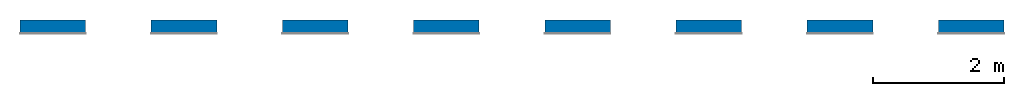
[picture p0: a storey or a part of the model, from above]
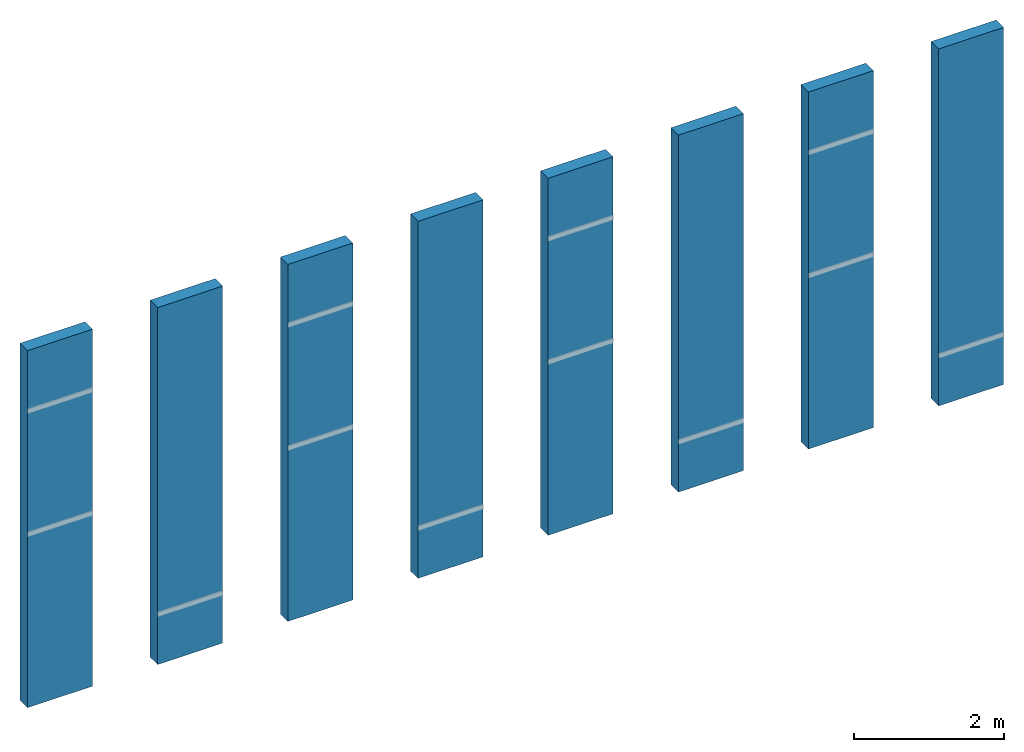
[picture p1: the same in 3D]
Properties of the parts of a building model (IFC4)

# File
Description: ViewDefinition [ReferenceView_V1.2], RevitIdentifiers [VersionGUID: 3b37235f-c921-4a61-a22a-4a3052ba0063, NumberOfSaves: 73], CoordinateReference [CoordinateBase: Shared Coordinates, ProjectSite: Internal]
File name: LOVE TILES-SENSE-SKIRTING.ifc
Time: 2025-04-01T11:52:26
Written by: ODA IFC SDK 22.8
Made in: 22.1.80.32 - IFC 22.7.0.0 - Default UI

# IfcSite, Default
RefLatitude: 42, 24, 53, 508911; RefLongitude: -71, -15, -29, -58837; RefElevation: 0 mm
Text - Library Version: V01
Identity Data - Author: StratBIM; Organization Description: CERAMIC TILES; Organization Name: MARGRES
Other - Category: Project Information; Project Issue Date: 01/2025

# IfcBuilding
Text - Library Version: V01
Identity Data - Author: StratBIM; Organization Description: CERAMIC TILES; Organization Name: MARGRES
Other - Category: Project Information; Project Issue Date: 01/2025

# IfcBuildingStorey: Level:Level 1, Level 1
LongName: Level 1; Elevation: 0 mm
Constraints - Elevation: 0 mm
Dimensions - Computation Height: 0 mm
Identity Data - Structural: no; Building Story: yes; Name: Level 1
Other - Category: Levels; Family: Level; Family and Type: Level: Level 1; Type: Level 1; Type Id: 1604
Constraints(Type) - Elevation Base: Project Base Point
Graphics(Type) - Color: 0; Line Pattern: Solid; Line Weight: 1; Symbol at End 1 Default: no; Symbol at End 2 Default: yes
Identity Data(Type) - Type Name: Level 1
Other(Type) - Category: Levels; Family Name: Level

# IfcBuildingElementProxy: Wall Sweep:LOVE TILES-SENSE-SKIRTING-8X100-IN&OUT RECTIFIED-BEIGE, Wall Sweep:LOVE TILES-SENSE-SKIRTING-8X100-IN&OUT RECTIFIED-BEIGE:47854
In: Level 1
Type - General - BIM Modeler: StratBIM; BIM Modeler URL: www.stratbim.com
Type - Analysis Results - Length per Piece: 1001 mm
Type - Constraints - Cut by Inserts: yes; Cuts Wall: yes; Default Setback: 0 mm
Type - Materials and Finishes - Material: LOVE TILES-SENSE-SKIRTING-8X100-IN&OUT RECTIFIED-BEIGE
Type - Construction - Profile: LOVE TILES-SENSE-SKIRTING-PROFILES : 8x100
Type - Identity Data - Manufacturer: LOVE TILES; Manufacturer URL: https://lovetiles.com/pt; Model: LOVE TILES-SENSE-SKIRTING-8X100-IN&OUT RECTIFIED-BEIGE; Publication date: 01/20025; Type Name: LOVE TILES-SENSE-SKIRTING-8X100-IN&OUT RECTIFIED-BEIGE; URL: https://lovetiles.com/en/products/sense; Version: V01
Type - Other - Category: Walls: Wall Sweeps; Family Name: Wall Sweep
Material: LOVE TILES-SENSE-SKIRTING-8X100-IN&OUT RECTIFIED-BEIGE
Constraints - Level: Level 1; Offset From Wall: 0 mm; Offset From Level: 780 mm
Phasing - Phase Created: New Construction
Dimensions - Length: 1000 mm
Other - Family: Wall Sweep; Family and Type: Wall Sweep: LOVE TILES-SENSE-SKIRTING-8X100-IN&OUT RECTIFIED-BEIGE; Type: LOVE TILES-SENSE-SKIRTING-8X100-IN&OUT RECTIFIED-BEIGE; Type Id: 54826

# IfcBuildingElementProxy: Wall Sweep:LOVE TILES-SENSE-SKIRTING-8X100-IN&OUT RECTIFIED-GREY, Wall Sweep:LOVE TILES-SENSE-SKIRTING-8X100-IN&OUT RECTIFIED-GREY:54863
In: Level 1
Type - General - BIM Modeler: StratBIM; BIM Modeler URL: www.stratbim.com
Type - Analysis Results - Length per Piece: 1001 mm
Type - Constraints - Cut by Inserts: yes; Cuts Wall: yes; Default Setback: 0 mm
Type - Materials and Finishes - Material: LOVE TILES-SENSE-SKIRTING-8X100-IN&OUT RECTIFIED-GREY
Type - Construction - Profile: LOVE TILES-SENSE-SKIRTING-PROFILES : 8x100
Type - Identity Data - Manufacturer: LOVE TILES; Manufacturer URL: https://lovetiles.com/pt; Model: LOVE TILES-SENSE-SKIRTING-8X100-IN&OUT RECTIFIED-GREY; Publication date: 01/20025; Type Name: LOVE TILES-SENSE-SKIRTING-8X100-IN&OUT RECTIFIED-GREY; URL: https://lovetiles.com/en/products/sense; Version: V01
Type - Other - Category: Walls: Wall Sweeps; Family Name: Wall Sweep
Material: LOVE TILES-SENSE-SKIRTING-8X100-IN&OUT RECTIFIED-GREY
Constraints - Level: Level 1; Offset From Wall: 0 mm; Offset From Level: 780 mm
Phasing - Phase Created: New Construction
Dimensions - Length: 1000 mm
Other - Family: Wall Sweep; Family and Type: Wall Sweep: LOVE TILES-SENSE-SKIRTING-8X100-IN&OUT RECTIFIED-GREY; Type: LOVE TILES-SENSE-SKIRTING-8X100-IN&OUT RECTIFIED-GREY; Type Id: 54900

# IfcBuildingElementProxy: Wall Sweep:LOVE TILES-SENSE-SKIRTING-8X100-IN&OUT RECTIFIED-LIGHT GREY, Wall Sweep:LOVE TILES-SENSE-SKIRTING-8X100-IN&OUT RECTIFIED-LIGHT GREY:54872
In: Level 1
Type - General - BIM Modeler: StratBIM; BIM Modeler URL: www.stratbim.com
Type - Analysis Results - Length per Piece: 1001 mm
Type - Constraints - Cut by Inserts: yes; Cuts Wall: yes; Default Setback: 0 mm
Type - Materials and Finishes - Material: LOVE TILES-SENSE-SKIRTING-8X100-IN&OUT RECTIFIED-LIGHT GREY
Type - Construction - Profile: LOVE TILES-SENSE-SKIRTING-PROFILES : 8x100
Type - Identity Data - Manufacturer: LOVE TILES; Manufacturer URL: https://lovetiles.com/pt; Model: LOVE TILES-SENSE-SKIRTING-8X100-IN&OUT RECTIFIED-LIGHT GREY; Publication date: 01/20025; Type Name: LOVE TILES-SENSE-SKIRTING-8X100-IN&OUT RECTIFIED-LIGHT GREY; URL: https://lovetiles.com/en/products/sense; Version: V01
Type - Other - Category: Walls: Wall Sweeps; Family Name: Wall Sweep
Material: LOVE TILES-SENSE-SKIRTING-8X100-IN&OUT RECTIFIED-LIGHT GREY
Constraints - Level: Level 1; Offset From Wall: 0 mm; Offset From Level: 780 mm
Phasing - Phase Created: New Construction
Dimensions - Length: 1000 mm
Other - Family: Wall Sweep; Family and Type: Wall Sweep: LOVE TILES-SENSE-SKIRTING-8X100-IN&OUT RECTIFIED-LIGHT GREY; Type: LOVE TILES-SENSE-SKIRTING-8X100-IN&OUT RECTIFIED-LIGHT GREY; Type Id: 54948

# IfcBuildingElementProxy: Wall Sweep:LOVE TILES-SENSE-SKIRTING-8X100-IN&OUT RECTIFIED-WHITE, Wall Sweep:LOVE TILES-SENSE-SKIRTING-8X100-IN&OUT RECTIFIED-WHITE:54881
In: Level 1
Type - General - BIM Modeler: StratBIM; BIM Modeler URL: www.stratbim.com
Type - Analysis Results - Length per Piece: 1001 mm
Type - Constraints - Cut by Inserts: yes; Cuts Wall: yes; Default Setback: 0 mm
Type - Materials and Finishes - Material: LOVE TILES-SENSE-SKIRTING-8X100-IN&OUT RECTIFIED-WHITE
Type - Construction - Profile: LOVE TILES-SENSE-SKIRTING-PROFILES : 8x100
Type - Identity Data - Manufacturer: LOVE TILES; Manufacturer URL: https://lovetiles.com/pt; Model: LOVE TILES-SENSE-SKIRTING-8X100-IN&OUT RECTIFIED-WHITE; Publication date: 01/20025; Type Name: LOVE TILES-SENSE-SKIRTING-8X100-IN&OUT RECTIFIED-WHITE; URL: https://lovetiles.com/en/products/sense; Version: V01
Type - Other - Category: Walls: Wall Sweeps; Family Name: Wall Sweep
Material: LOVE TILES-SENSE-SKIRTING-8X100-IN&OUT RECTIFIED-WHITE
Constraints - Level: Level 1; Offset From Wall: 0 mm; Offset From Level: 780 mm
Phasing - Phase Created: New Construction
Dimensions - Length: 1000 mm
Other - Family: Wall Sweep; Family and Type: Wall Sweep: LOVE TILES-SENSE-SKIRTING-8X100-IN&OUT RECTIFIED-WHITE; Type: LOVE TILES-SENSE-SKIRTING-8X100-IN&OUT RECTIFIED-WHITE; Type Id: 54966

# IfcBuildingElementProxy: Wall Sweep:LOVE TILES-SENSE-SKIRTING-8X60-TOUCH RECTIFIED-BEIGE, Wall Sweep:LOVE TILES-SENSE-SKIRTING-8X60-TOUCH RECTIFIED-BEIGE:41320
In: Level 1
Type - General - BIM Modeler: StratBIM; BIM Modeler URL: www.stratbim.com
Type - Analysis Results - Length per Piece: 600 mm
Type - Constraints - Cut by Inserts: yes; Cuts Wall: yes; Default Setback: 0 mm
Type - Materials and Finishes - Material: LOVE TILES-SENSE-SKIRTING-8X60-TOUCH RECTIFIED-BEIGE
Type - Construction - Profile: LOVE TILES-SENSE-SKIRTING-PROFILES : 8x60
Type - Identity Data - Manufacturer: LOVE TILES; Manufacturer URL: https://lovetiles.com/pt; Model: LOVE TILES-SENSE-SKIRTING-8X60-TOUCH RECTIFIED-BEIGE; Publication date: 01/20025; Reference: 661.0088.002; Type Name: LOVE TILES-SENSE-SKIRTING-8X60-TOUCH RECTIFIED-BEIGE; URL: https://lovetiles.com/en/products/sense; Version: V01
Type - Other - Category: Walls: Wall Sweeps; Family Name: Wall Sweep
Material: LOVE TILES-SENSE-SKIRTING-8X60-TOUCH RECTIFIED-BEIGE
Constraints - Level: Level 1; Offset From Level: 4780 mm; Offset From Wall: 0 mm
Phasing - Phase Created: New Construction
Dimensions - Length: 1000 mm
Other - Family: Wall Sweep; Family and Type: Wall Sweep: LOVE TILES-SENSE-SKIRTING-8X60-TOUCH RECTIFIED-BEIGE; Type: LOVE TILES-SENSE-SKIRTING-8X60-TOUCH RECTIFIED-BEIGE; Type Id: 54612

# IfcBuildingElementProxy: Wall Sweep:LOVE TILES-SENSE-SKIRTING-8X60-TOUCH RECTIFIED-GREY, Wall Sweep:LOVE TILES-SENSE-SKIRTING-8X60-TOUCH RECTIFIED-GREY:48028
In: Level 1
Type - General - BIM Modeler: StratBIM; BIM Modeler URL: www.stratbim.com
Type - Analysis Results - Length per Piece: 600 mm
Type - Constraints - Cut by Inserts: yes; Cuts Wall: yes; Default Setback: 0 mm
Type - Materials and Finishes - Material: LOVE TILES-SENSE-SKIRTING-8X60-TOUCH RECTIFIED-GREY
Type - Construction - Profile: LOVE TILES-SENSE-SKIRTING-PROFILES : 8x60
Type - Identity Data - Manufacturer: LOVE TILES; Manufacturer URL: https://lovetiles.com/pt; Model: LOVE TILES-SENSE-SKIRTING-8X60-TOUCH RECTIFIED-GREY; Publication date: 01/20025; Reference: 661.0088.003; Type Name: LOVE TILES-SENSE-SKIRTING-8X60-TOUCH RECTIFIED-GREY; URL: https://lovetiles.com/en/products/sense; Version: V01
Type - Other - Category: Walls: Wall Sweeps; Family Name: Wall Sweep
Material: LOVE TILES-SENSE-SKIRTING-8X60-TOUCH RECTIFIED-GREY
Constraints - Level: Level 1; Offset From Wall: 0 mm; Offset From Level: 4780 mm
Phasing - Phase Created: New Construction
Dimensions - Length: 1000 mm
Other - Family: Wall Sweep; Family and Type: Wall Sweep: LOVE TILES-SENSE-SKIRTING-8X60-TOUCH RECTIFIED-GREY; Type: LOVE TILES-SENSE-SKIRTING-8X60-TOUCH RECTIFIED-GREY; Type Id: 54499

# IfcBuildingElementProxy: Wall Sweep:LOVE TILES-SENSE-SKIRTING-8X60-TOUCH RECTIFIED-LIGHT GREY, Wall Sweep:LOVE TILES-SENSE-SKIRTING-8X60-TOUCH RECTIFIED-LIGHT GREY:48154
In: Level 1
Type - General - BIM Modeler: StratBIM; BIM Modeler URL: www.stratbim.com
Type - Analysis Results - Length per Piece: 600 mm
Type - Constraints - Cut by Inserts: yes; Cuts Wall: yes; Default Setback: 0 mm
Type - Materials and Finishes - Material: LOVE TILES-SENSE-SKIRTING-8X60-TOUCH RECTIFIED-LIGHT GREY
Type - Construction - Profile: LOVE TILES-SENSE-SKIRTING-PROFILES : 8x60
Type - Identity Data - Manufacturer: LOVE TILES; Manufacturer URL: https://lovetiles.com/pt; Model: LOVE TILES-SENSE-SKIRTING-8X60-TOUCH RECTIFIED-LIGHT GREY; Publication date: 01/20025; Reference: 661.0088.047; Type Name: LOVE TILES-SENSE-SKIRTING-8X60-TOUCH RECTIFIED-LIGHT GREY; URL: https://lovetiles.com/en/products/sense; Version: V01
Type - Other - Category: Walls: Wall Sweeps; Family Name: Wall Sweep
Material: LOVE TILES-SENSE-SKIRTING-8X60-TOUCH RECTIFIED-LIGHT GREY
Constraints - Level: Level 1; Offset From Wall: 0 mm; Offset From Level: 4780 mm
Phasing - Phase Created: New Construction
Dimensions - Length: 1000 mm
Other - Family: Wall Sweep; Family and Type: Wall Sweep: LOVE TILES-SENSE-SKIRTING-8X60-TOUCH RECTIFIED-LIGHT GREY; Type: LOVE TILES-SENSE-SKIRTING-8X60-TOUCH RECTIFIED-LIGHT GREY; Type Id: 54517

# IfcBuildingElementProxy: Wall Sweep:LOVE TILES-SENSE-SKIRTING-8X60-TOUCH RECTIFIED-WHITE, Wall Sweep:LOVE TILES-SENSE-SKIRTING-8X60-TOUCH RECTIFIED-WHITE:50263
In: Level 1
Type - General - BIM Modeler: StratBIM; BIM Modeler URL: www.stratbim.com
Type - Analysis Results - Length per Piece: 600 mm
Type - Constraints - Cut by Inserts: yes; Cuts Wall: yes; Default Setback: 0 mm
Type - Materials and Finishes - Material: LOVE TILES-SENSE-SKIRTING-8X60-TOUCH RECTIFIED-WHITE
Type - Construction - Profile: LOVE TILES-SENSE-SKIRTING-PROFILES : 8x60
Type - Identity Data - Manufacturer: LOVE TILES; Manufacturer URL: https://lovetiles.com/pt; Model: LOVE TILES-SENSE-SKIRTING-8X60-TOUCH RECTIFIED-WHITE; Publication date: 01/20025; Reference: 661.0088.001; Type Name: LOVE TILES-SENSE-SKIRTING-8X60-TOUCH RECTIFIED-WHITE; URL: https://lovetiles.com/en/products/sense; Version: V01
Type - Other - Category: Walls: Wall Sweeps; Family Name: Wall Sweep
Material: LOVE TILES-SENSE-SKIRTING-8X60-TOUCH RECTIFIED-WHITE
Constraints - Level: Level 1; Offset From Wall: 0 mm; Offset From Level: 4780 mm
Phasing - Phase Created: New Construction
Dimensions - Length: 1000 mm
Other - Family: Wall Sweep; Family and Type: Wall Sweep: LOVE TILES-SENSE-SKIRTING-8X60-TOUCH RECTIFIED-WHITE; Type: LOVE TILES-SENSE-SKIRTING-8X60-TOUCH RECTIFIED-WHITE; Type Id: 46005

# IfcBuildingElementProxy: Wall Sweep:LOVE TILES-SENSE-SKIRTING-8X80-TOUCH RECTIFIED-BEIGE, Wall Sweep:LOVE TILES-SENSE-SKIRTING-8X80-TOUCH RECTIFIED-BEIGE:47761
In: Level 1
Type - General - BIM Modeler: StratBIM; BIM Modeler URL: www.stratbim.com
Type - Analysis Results - Length per Piece: 802 mm
Type - Constraints - Cut by Inserts: yes; Cuts Wall: yes; Default Setback: 0 mm
Type - Materials and Finishes - Material: LOVE TILES-SENSE-SKIRTING-8X80-TOUCH RECTIFIED-BEIGE
Type - Construction - Profile: LOVE TILES-SENSE-SKIRTING-PROFILES : 8x80
Type - Identity Data - Manufacturer: LOVE TILES; Manufacturer URL: https://lovetiles.com/pt; Model: LOVE TILES-SENSE-SKIRTING-8X80-TOUCH RECTIFIED-BEIGE; Publication date: 01/20025; Reference: 661.0087.002; Type Name: LOVE TILES-SENSE-SKIRTING-8X80-TOUCH RECTIFIED-BEIGE; URL: https://lovetiles.com/en/products/sense; Version: V01
Type - Other - Category: Walls: Wall Sweeps; Family Name: Wall Sweep
Material: LOVE TILES-SENSE-SKIRTING-8X80-TOUCH RECTIFIED-BEIGE
Constraints - Level: Level 1; Offset From Wall: 0 mm; Offset From Level: 2780 mm
Phasing - Phase Created: New Construction
Dimensions - Length: 1000 mm
Other - Family: Wall Sweep; Family and Type: Wall Sweep: LOVE TILES-SENSE-SKIRTING-8X80-TOUCH RECTIFIED-BEIGE; Type: LOVE TILES-SENSE-SKIRTING-8X80-TOUCH RECTIFIED-BEIGE; Type Id: 54633

# IfcBuildingElementProxy: Wall Sweep:LOVE TILES-SENSE-SKIRTING-8X80-TOUCH RECTIFIED-GREY, Wall Sweep:LOVE TILES-SENSE-SKIRTING-8X80-TOUCH RECTIFIED-GREY:54675
In: Level 1
Type - General - BIM Modeler: StratBIM; BIM Modeler URL: www.stratbim.com
Type - Analysis Results - Length per Piece: 802 mm
Type - Constraints - Cut by Inserts: yes; Cuts Wall: yes; Default Setback: 0 mm
Type - Materials and Finishes - Material: LOVE TILES-SENSE-SKIRTING-8X80-TOUCH RECTIFIED-GREY
Type - Construction - Profile: LOVE TILES-SENSE-SKIRTING-PROFILES : 8x80
Type - Identity Data - Manufacturer: LOVE TILES; Manufacturer URL: https://lovetiles.com/pt; Model: LOVE TILES-SENSE-SKIRTING-8X80-TOUCH RECTIFIED-GREY; Publication date: 01/20025; Reference: 661.0087.003; Type Name: LOVE TILES-SENSE-SKIRTING-8X80-TOUCH RECTIFIED-GREY; URL: https://lovetiles.com/en/products/sense; Version: V01
Type - Other - Category: Walls: Wall Sweeps; Family Name: Wall Sweep
Material: LOVE TILES-SENSE-SKIRTING-8X80-TOUCH RECTIFIED-GREY
Constraints - Level: Level 1; Offset From Wall: 0 mm; Offset From Level: 2780 mm
Phasing - Phase Created: New Construction
Dimensions - Length: 1000 mm
Other - Family: Wall Sweep; Family and Type: Wall Sweep: LOVE TILES-SENSE-SKIRTING-8X80-TOUCH RECTIFIED-GREY; Type: LOVE TILES-SENSE-SKIRTING-8X80-TOUCH RECTIFIED-GREY; Type Id: 54747

# IfcBuildingElementProxy: Wall Sweep:LOVE TILES-SENSE-SKIRTING-8X80-TOUCH RECTIFIED-LIGHT GREY, Wall Sweep:LOVE TILES-SENSE-SKIRTING-8X80-TOUCH RECTIFIED-LIGHT GREY:54684
In: Level 1
Type - General - BIM Modeler: StratBIM; BIM Modeler URL: www.stratbim.com
Type - Analysis Results - Length per Piece: 802 mm
Type - Constraints - Cut by Inserts: yes; Cuts Wall: yes; Default Setback: 0 mm
Type - Materials and Finishes - Material: LOVE TILES-SENSE-SKIRTING-8X80-TOUCH RECTIFIED-LIGHT GREY
Type - Construction - Profile: LOVE TILES-SENSE-SKIRTING-PROFILES : 8x80
Type - Identity Data - Manufacturer: LOVE TILES; Manufacturer URL: https://lovetiles.com/pt; Model: LOVE TILES-SENSE-SKIRTING-8X80-TOUCH RECTIFIED-LIGHT GREY; Publication date: 01/20025; Reference: 661.0087.047; Type Name: LOVE TILES-SENSE-SKIRTING-8X80-TOUCH RECTIFIED-LIGHT GREY; URL: https://lovetiles.com/en/products/sense; Version: V01
Type - Other - Category: Walls: Wall Sweeps; Family Name: Wall Sweep
Material: LOVE TILES-SENSE-SKIRTING-8X80-TOUCH RECTIFIED-LIGHT GREY
Constraints - Level: Level 1; Offset From Wall: 0 mm; Offset From Level: 2780 mm
Phasing - Phase Created: New Construction
Dimensions - Length: 1000 mm
Other - Family: Wall Sweep; Family and Type: Wall Sweep: LOVE TILES-SENSE-SKIRTING-8X80-TOUCH RECTIFIED-LIGHT GREY; Type: LOVE TILES-SENSE-SKIRTING-8X80-TOUCH RECTIFIED-LIGHT GREY; Type Id: 54765

# IfcBuildingElementProxy: Wall Sweep:LOVE TILES-SENSE-SKIRTING-8X80-TOUCH RECTIFIED-WHITE, Wall Sweep:LOVE TILES-SENSE-SKIRTING-8X80-TOUCH RECTIFIED-WHITE:54693
In: Level 1
Type - General - BIM Modeler: StratBIM; BIM Modeler URL: www.stratbim.com
Type - Analysis Results - Length per Piece: 802 mm
Type - Constraints - Cut by Inserts: yes; Cuts Wall: yes; Default Setback: 0 mm
Type - Materials and Finishes - Material: LOVE TILES-SENSE-SKIRTING-8X80-TOUCH RECTIFIED-WHITE
Type - Construction - Profile: LOVE TILES-SENSE-SKIRTING-PROFILES : 8x80
Type - Identity Data - Manufacturer: LOVE TILES; Manufacturer URL: https://lovetiles.com/pt; Model: LOVE TILES-SENSE-SKIRTING-8X80-TOUCH RECTIFIED-WHITE; Publication date: 01/20025; Reference: 661.0087.001; Type Name: LOVE TILES-SENSE-SKIRTING-8X80-TOUCH RECTIFIED-WHITE; URL: https://lovetiles.com/en/products/sense; Version: V01
Type - Other - Category: Walls: Wall Sweeps; Family Name: Wall Sweep
Material: LOVE TILES-SENSE-SKIRTING-8X80-TOUCH RECTIFIED-WHITE
Constraints - Level: Level 1; Offset From Wall: 0 mm; Offset From Level: 2780 mm
Phasing - Phase Created: New Construction
Dimensions - Length: 1000 mm
Other - Family: Wall Sweep; Family and Type: Wall Sweep: LOVE TILES-SENSE-SKIRTING-8X80-TOUCH RECTIFIED-WHITE; Type: LOVE TILES-SENSE-SKIRTING-8X80-TOUCH RECTIFIED-WHITE; Type Id: 54783

# IfcWall: Basic Wall:Wall 1 (8)
In: Level 1
Type - PredefinedType: STANDARD
Type - Analytical Properties - Absorptance: 0.1; Roughness: 1
Type - Graphics - Coarse Scale Fill Color: 0
Type - Construction - Function: Exterior; Width: 200 mm; Wrapping at Inserts: Do not wrap
Type - Identity Data - Type Name: Wall 1
Type - Other - Category: Walls; Family Name: Basic Wall
Material: <Unnamed>
Cross-Section Definition - Cross-Section: Vertical
Constraints - Base Constraint: Level 1; Base Extension Distance: 0 mm; Base is Attached: no; Base Offset: 0 mm; Location Line: Wall Centerline; Related to Mass: no; Room Bounding: yes; Top Extension Distance: 0 mm; Top is Attached: no; Top Offset: 0 mm; Unconnected Height: 5800 mm
Phasing - Phase Created: New Construction
Structural - Enable Analytical Model: no; Structural: no; Structural Usage: Non-bearing
Dimensions - Area: 5.8 m2; Length: 1000 mm; Volume: 1.16 m3
Other - Family: Basic Wall; Family and Type: Basic Wall: Wall 1; Type: Wall 1; Type Id: 49975
Name (Basic Wall:Wall 1:...)
41280
47851
48027
48031
48153
48157
48269
48273
